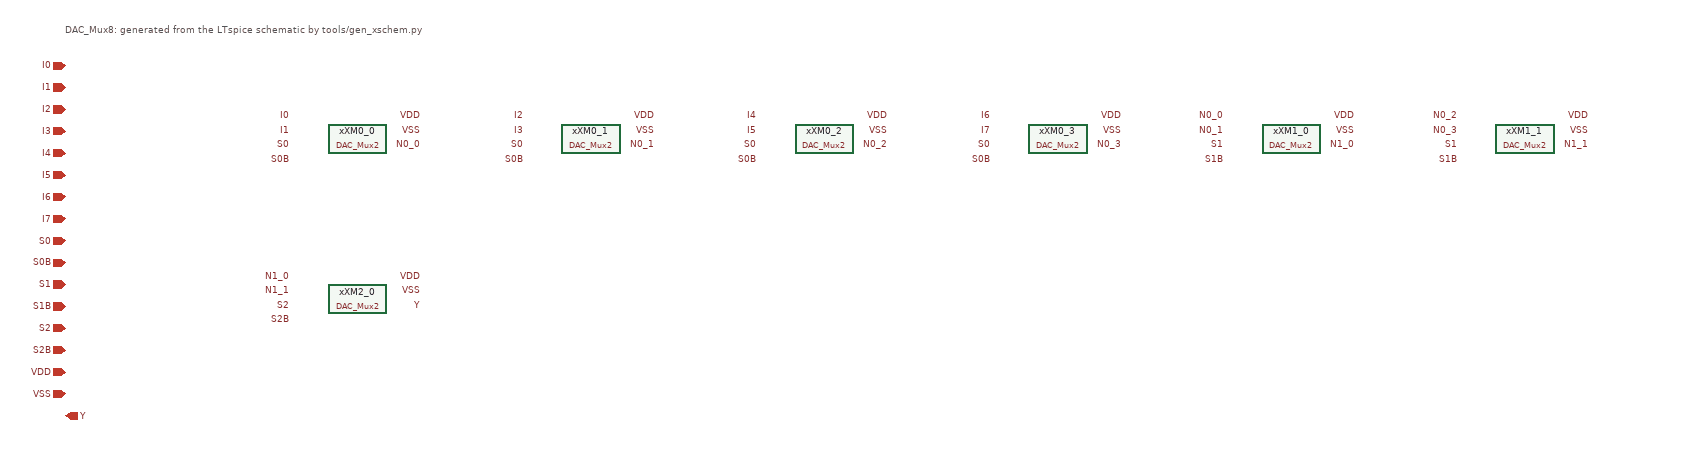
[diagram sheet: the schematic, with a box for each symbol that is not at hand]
v {xschem version=3.4.4 file_version=1.2
}
G {}
K {}
V {}
S {}
E {}
T {DAC_Mux8: generated from the LTspice schematic by tools/gen_xschem.py} -900 -560 0 0 0.4 0.4 {}
C {devices/ipin.sym} -900 -500 0 0 {name=p1 lab=I0}
C {devices/ipin.sym} -900 -470 0 0 {name=p2 lab=I1}
C {devices/ipin.sym} -900 -440 0 0 {name=p3 lab=I2}
C {devices/ipin.sym} -900 -410 0 0 {name=p4 lab=I3}
C {devices/ipin.sym} -900 -380 0 0 {name=p5 lab=I4}
C {devices/ipin.sym} -900 -350 0 0 {name=p6 lab=I5}
C {devices/ipin.sym} -900 -320 0 0 {name=p7 lab=I6}
C {devices/ipin.sym} -900 -290 0 0 {name=p8 lab=I7}
C {devices/ipin.sym} -900 -260 0 0 {name=p9 lab=S0}
C {devices/ipin.sym} -900 -230 0 0 {name=p10 lab=S0B}
C {devices/ipin.sym} -900 -200 0 0 {name=p11 lab=S1}
C {devices/ipin.sym} -900 -170 0 0 {name=p12 lab=S1B}
C {devices/ipin.sym} -900 -140 0 0 {name=p13 lab=S2}
C {devices/ipin.sym} -900 -110 0 0 {name=p14 lab=S2B}
C {devices/iopin.sym} -900 -80 0 0 {name=p15 lab=VDD}
C {devices/iopin.sym} -900 -50 0 0 {name=p16 lab=VSS}
C {devices/opin.sym} -900 -20 0 0 {name=p17 lab=Y}
C {DAC_Mux2.sym} -500 -400 0 0 {name=xXM0_0}
C {devices/lab_pin.sym} -590.0 -430.0 0 0 {name=l1 sig_type=std_logic lab=I0}
C {devices/lab_pin.sym} -590.0 -410.0 0 0 {name=l2 sig_type=std_logic lab=I1}
C {devices/lab_pin.sym} -590.0 -390.0 0 0 {name=l3 sig_type=std_logic lab=S0}
C {devices/lab_pin.sym} -590.0 -370.0 0 0 {name=l4 sig_type=std_logic lab=S0B}
C {devices/lab_pin.sym} -410.0 -430.0 0 0 {name=l5 sig_type=std_logic lab=VDD}
C {devices/lab_pin.sym} -410.0 -410.0 0 0 {name=l6 sig_type=std_logic lab=VSS}
C {devices/lab_pin.sym} -410.0 -390.0 0 0 {name=l7 sig_type=std_logic lab=N0_0}
C {DAC_Mux2.sym} -180 -400 0 0 {name=xXM0_1}
C {devices/lab_pin.sym} -270.0 -430.0 0 0 {name=l8 sig_type=std_logic lab=I2}
C {devices/lab_pin.sym} -270.0 -410.0 0 0 {name=l9 sig_type=std_logic lab=I3}
C {devices/lab_pin.sym} -270.0 -390.0 0 0 {name=l10 sig_type=std_logic lab=S0}
C {devices/lab_pin.sym} -270.0 -370.0 0 0 {name=l11 sig_type=std_logic lab=S0B}
C {devices/lab_pin.sym} -90.0 -430.0 0 0 {name=l12 sig_type=std_logic lab=VDD}
C {devices/lab_pin.sym} -90.0 -410.0 0 0 {name=l13 sig_type=std_logic lab=VSS}
C {devices/lab_pin.sym} -90.0 -390.0 0 0 {name=l14 sig_type=std_logic lab=N0_1}
C {DAC_Mux2.sym} 140 -400 0 0 {name=xXM0_2}
C {devices/lab_pin.sym} 50.0 -430.0 0 0 {name=l15 sig_type=std_logic lab=I4}
C {devices/lab_pin.sym} 50.0 -410.0 0 0 {name=l16 sig_type=std_logic lab=I5}
C {devices/lab_pin.sym} 50.0 -390.0 0 0 {name=l17 sig_type=std_logic lab=S0}
C {devices/lab_pin.sym} 50.0 -370.0 0 0 {name=l18 sig_type=std_logic lab=S0B}
C {devices/lab_pin.sym} 230.0 -430.0 0 0 {name=l19 sig_type=std_logic lab=VDD}
C {devices/lab_pin.sym} 230.0 -410.0 0 0 {name=l20 sig_type=std_logic lab=VSS}
C {devices/lab_pin.sym} 230.0 -390.0 0 0 {name=l21 sig_type=std_logic lab=N0_2}
C {DAC_Mux2.sym} 460 -400 0 0 {name=xXM0_3}
C {devices/lab_pin.sym} 370.0 -430.0 0 0 {name=l22 sig_type=std_logic lab=I6}
C {devices/lab_pin.sym} 370.0 -410.0 0 0 {name=l23 sig_type=std_logic lab=I7}
C {devices/lab_pin.sym} 370.0 -390.0 0 0 {name=l24 sig_type=std_logic lab=S0}
C {devices/lab_pin.sym} 370.0 -370.0 0 0 {name=l25 sig_type=std_logic lab=S0B}
C {devices/lab_pin.sym} 550.0 -430.0 0 0 {name=l26 sig_type=std_logic lab=VDD}
C {devices/lab_pin.sym} 550.0 -410.0 0 0 {name=l27 sig_type=std_logic lab=VSS}
C {devices/lab_pin.sym} 550.0 -390.0 0 0 {name=l28 sig_type=std_logic lab=N0_3}
C {DAC_Mux2.sym} 780 -400 0 0 {name=xXM1_0}
C {devices/lab_pin.sym} 690.0 -430.0 0 0 {name=l29 sig_type=std_logic lab=N0_0}
C {devices/lab_pin.sym} 690.0 -410.0 0 0 {name=l30 sig_type=std_logic lab=N0_1}
C {devices/lab_pin.sym} 690.0 -390.0 0 0 {name=l31 sig_type=std_logic lab=S1}
C {devices/lab_pin.sym} 690.0 -370.0 0 0 {name=l32 sig_type=std_logic lab=S1B}
C {devices/lab_pin.sym} 870.0 -430.0 0 0 {name=l33 sig_type=std_logic lab=VDD}
C {devices/lab_pin.sym} 870.0 -410.0 0 0 {name=l34 sig_type=std_logic lab=VSS}
C {devices/lab_pin.sym} 870.0 -390.0 0 0 {name=l35 sig_type=std_logic lab=N1_0}
C {DAC_Mux2.sym} 1100 -400 0 0 {name=xXM1_1}
C {devices/lab_pin.sym} 1010.0 -430.0 0 0 {name=l36 sig_type=std_logic lab=N0_2}
C {devices/lab_pin.sym} 1010.0 -410.0 0 0 {name=l37 sig_type=std_logic lab=N0_3}
C {devices/lab_pin.sym} 1010.0 -390.0 0 0 {name=l38 sig_type=std_logic lab=S1}
C {devices/lab_pin.sym} 1010.0 -370.0 0 0 {name=l39 sig_type=std_logic lab=S1B}
C {devices/lab_pin.sym} 1190.0 -430.0 0 0 {name=l40 sig_type=std_logic lab=VDD}
C {devices/lab_pin.sym} 1190.0 -410.0 0 0 {name=l41 sig_type=std_logic lab=VSS}
C {devices/lab_pin.sym} 1190.0 -390.0 0 0 {name=l42 sig_type=std_logic lab=N1_1}
C {DAC_Mux2.sym} -500 -180 0 0 {name=xXM2_0}
C {devices/lab_pin.sym} -590.0 -210.0 0 0 {name=l43 sig_type=std_logic lab=N1_0}
C {devices/lab_pin.sym} -590.0 -190.0 0 0 {name=l44 sig_type=std_logic lab=N1_1}
C {devices/lab_pin.sym} -590.0 -170.0 0 0 {name=l45 sig_type=std_logic lab=S2}
C {devices/lab_pin.sym} -590.0 -150.0 0 0 {name=l46 sig_type=std_logic lab=S2B}
C {devices/lab_pin.sym} -410.0 -210.0 0 0 {name=l47 sig_type=std_logic lab=VDD}
C {devices/lab_pin.sym} -410.0 -190.0 0 0 {name=l48 sig_type=std_logic lab=VSS}
C {devices/lab_pin.sym} -410.0 -170.0 0 0 {name=l49 sig_type=std_logic lab=Y}
